# Generated by OpenFakeRAM
VERSION 5.7 ;
BUSBITCHARS "[]" ;
PROPERTYDEFINITIONS
  MACRO width INTEGER ;
  MACRO depth INTEGER ;
  MACRO banks INTEGER ;
END PROPERTYDEFINITIONS
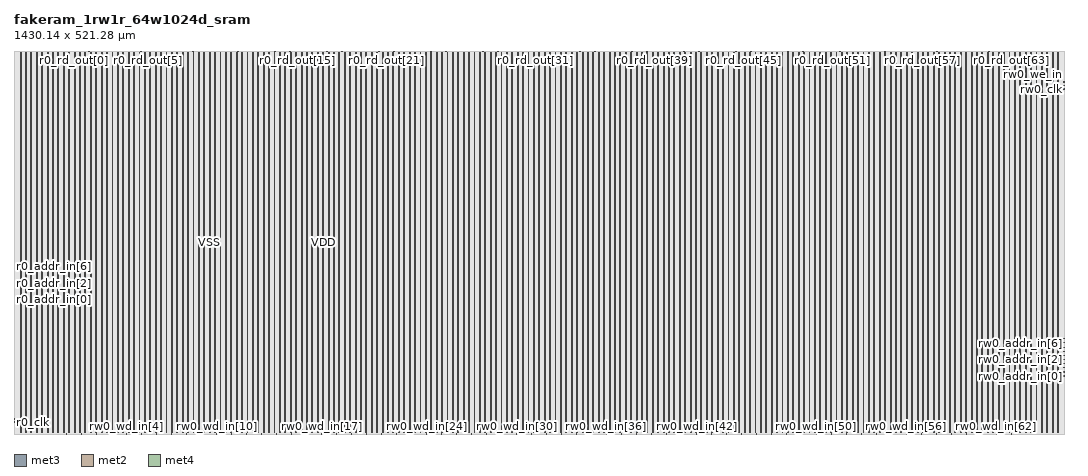
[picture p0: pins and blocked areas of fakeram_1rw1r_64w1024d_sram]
MACRO fakeram_1rw1r_64w1024d_sram
  PROPERTY width 64 ;
  PROPERTY depth 1024 ;
  PROPERTY banks 1 ;
  FOREIGN fakeram_1rw1r_64w1024d_sram 0 0 ;
  SYMMETRY X Y R90 ;
  SIZE 1430.140 BY 521.280 ;
  CLASS BLOCK ;
  PIN r0_clk
    DIRECTION INPUT ;
    USE SIGNAL ;
    SHAPE ABUTMENT ;
    PORT
      LAYER met3 ;
      RECT 0.000 16.170 0.800 16.470 ;
    END
  END r0_clk
  PIN r0_ce_in
    DIRECTION INPUT ;
    USE SIGNAL ;
    SHAPE ABUTMENT ;
    PORT
      LAYER met3 ;
      RECT 0.000 20.250 0.800 20.550 ;
    END
  END r0_ce_in
  PIN r0_addr_in[0]
    DIRECTION INPUT ;
    USE SIGNAL ;
    SHAPE ABUTMENT ;
    PORT
      LAYER met3 ;
      RECT 0.000 182.770 0.800 183.070 ;
    END
  END r0_addr_in[0]
  PIN r0_addr_in[1]
    DIRECTION INPUT ;
    USE SIGNAL ;
    SHAPE ABUTMENT ;
    PORT
      LAYER met3 ;
      RECT 0.000 188.210 0.800 188.510 ;
    END
  END r0_addr_in[1]
  PIN r0_addr_in[2]
    DIRECTION INPUT ;
    USE SIGNAL ;
    SHAPE ABUTMENT ;
    PORT
      LAYER met3 ;
      RECT 0.000 194.330 0.800 194.630 ;
    END
  END r0_addr_in[2]
  PIN r0_addr_in[3]
    DIRECTION INPUT ;
    USE SIGNAL ;
    SHAPE ABUTMENT ;
    PORT
      LAYER met3 ;
      RECT 0.000 199.770 0.800 200.070 ;
    END
  END r0_addr_in[3]
  PIN r0_addr_in[4]
    DIRECTION INPUT ;
    USE SIGNAL ;
    SHAPE ABUTMENT ;
    PORT
      LAYER met3 ;
      RECT 0.000 205.890 0.800 206.190 ;
    END
  END r0_addr_in[4]
  PIN r0_addr_in[5]
    DIRECTION INPUT ;
    USE SIGNAL ;
    SHAPE ABUTMENT ;
    PORT
      LAYER met3 ;
      RECT 0.000 211.330 0.800 211.630 ;
    END
  END r0_addr_in[5]
  PIN r0_addr_in[6]
    DIRECTION INPUT ;
    USE SIGNAL ;
    SHAPE ABUTMENT ;
    PORT
      LAYER met3 ;
      RECT 0.000 217.450 0.800 217.750 ;
    END
  END r0_addr_in[6]
  PIN r0_addr_in[7]
    DIRECTION INPUT ;
    USE SIGNAL ;
    SHAPE ABUTMENT ;
    PORT
      LAYER met3 ;
      RECT 0.000 222.890 0.800 223.190 ;
    END
  END r0_addr_in[7]
  PIN r0_addr_in[8]
    DIRECTION INPUT ;
    USE SIGNAL ;
    SHAPE ABUTMENT ;
    PORT
      LAYER met3 ;
      RECT 0.000 229.010 0.800 229.310 ;
    END
  END r0_addr_in[8]
  PIN r0_addr_in[9]
    DIRECTION INPUT ;
    USE SIGNAL ;
    SHAPE ABUTMENT ;
    PORT
      LAYER met3 ;
      RECT 0.000 234.450 0.800 234.750 ;
    END
  END r0_addr_in[9]
  PIN rw0_rd_out[0]
    DIRECTION OUTPUT ;
    USE SIGNAL ;
    SHAPE ABUTMENT ;
    PORT
      LAYER met2 ;
      RECT 71.610 520.480 71.910 521.280 ;
    END
  END rw0_rd_out[0]
  PIN r0_rd_out[0]
    DIRECTION OUTPUT ;
    USE SIGNAL ;
    SHAPE ABUTMENT ;
    PORT
      LAYER met2 ;
      RECT 81.730 520.480 82.030 521.280 ;
    END
  END r0_rd_out[0]
  PIN rw0_rd_out[1]
    DIRECTION OUTPUT ;
    USE SIGNAL ;
    SHAPE ABUTMENT ;
    PORT
      LAYER met2 ;
      RECT 91.850 520.480 92.150 521.280 ;
    END
  END rw0_rd_out[1]
  PIN r0_rd_out[1]
    DIRECTION OUTPUT ;
    USE SIGNAL ;
    SHAPE ABUTMENT ;
    PORT
      LAYER met2 ;
      RECT 101.970 520.480 102.270 521.280 ;
    END
  END r0_rd_out[1]
  PIN rw0_rd_out[2]
    DIRECTION OUTPUT ;
    USE SIGNAL ;
    SHAPE ABUTMENT ;
    PORT
      LAYER met2 ;
      RECT 112.090 520.480 112.390 521.280 ;
    END
  END rw0_rd_out[2]
  PIN r0_rd_out[2]
    DIRECTION OUTPUT ;
    USE SIGNAL ;
    SHAPE ABUTMENT ;
    PORT
      LAYER met2 ;
      RECT 122.210 520.480 122.510 521.280 ;
    END
  END r0_rd_out[2]
  PIN rw0_rd_out[3]
    DIRECTION OUTPUT ;
    USE SIGNAL ;
    SHAPE ABUTMENT ;
    PORT
      LAYER met2 ;
      RECT 132.330 520.480 132.630 521.280 ;
    END
  END rw0_rd_out[3]
  PIN r0_rd_out[3]
    DIRECTION OUTPUT ;
    USE SIGNAL ;
    SHAPE ABUTMENT ;
    PORT
      LAYER met2 ;
      RECT 142.450 520.480 142.750 521.280 ;
    END
  END r0_rd_out[3]
  PIN rw0_rd_out[4]
    DIRECTION OUTPUT ;
    USE SIGNAL ;
    SHAPE ABUTMENT ;
    PORT
      LAYER met2 ;
      RECT 152.570 520.480 152.870 521.280 ;
    END
  END rw0_rd_out[4]
  PIN r0_rd_out[4]
    DIRECTION OUTPUT ;
    USE SIGNAL ;
    SHAPE ABUTMENT ;
    PORT
      LAYER met2 ;
      RECT 162.690 520.480 162.990 521.280 ;
    END
  END r0_rd_out[4]
  PIN rw0_rd_out[5]
    DIRECTION OUTPUT ;
    USE SIGNAL ;
    SHAPE ABUTMENT ;
    PORT
      LAYER met2 ;
      RECT 172.810 520.480 173.110 521.280 ;
    END
  END rw0_rd_out[5]
  PIN r0_rd_out[5]
    DIRECTION OUTPUT ;
    USE SIGNAL ;
    SHAPE ABUTMENT ;
    PORT
      LAYER met2 ;
      RECT 182.930 520.480 183.230 521.280 ;
    END
  END r0_rd_out[5]
  PIN rw0_rd_out[6]
    DIRECTION OUTPUT ;
    USE SIGNAL ;
    SHAPE ABUTMENT ;
    PORT
      LAYER met2 ;
      RECT 193.050 520.480 193.350 521.280 ;
    END
  END rw0_rd_out[6]
  PIN r0_rd_out[6]
    DIRECTION OUTPUT ;
    USE SIGNAL ;
    SHAPE ABUTMENT ;
    PORT
      LAYER met2 ;
      RECT 203.170 520.480 203.470 521.280 ;
    END
  END r0_rd_out[6]
  PIN rw0_rd_out[7]
    DIRECTION OUTPUT ;
    USE SIGNAL ;
    SHAPE ABUTMENT ;
    PORT
      LAYER met2 ;
      RECT 213.290 520.480 213.590 521.280 ;
    END
  END rw0_rd_out[7]
  PIN r0_rd_out[7]
    DIRECTION OUTPUT ;
    USE SIGNAL ;
    SHAPE ABUTMENT ;
    PORT
      LAYER met2 ;
      RECT 223.410 520.480 223.710 521.280 ;
    END
  END r0_rd_out[7]
  PIN rw0_rd_out[8]
    DIRECTION OUTPUT ;
    USE SIGNAL ;
    SHAPE ABUTMENT ;
    PORT
      LAYER met2 ;
      RECT 233.530 520.480 233.830 521.280 ;
    END
  END rw0_rd_out[8]
  PIN r0_rd_out[8]
    DIRECTION OUTPUT ;
    USE SIGNAL ;
    SHAPE ABUTMENT ;
    PORT
      LAYER met2 ;
      RECT 243.650 520.480 243.950 521.280 ;
    END
  END r0_rd_out[8]
  PIN rw0_rd_out[9]
    DIRECTION OUTPUT ;
    USE SIGNAL ;
    SHAPE ABUTMENT ;
    PORT
      LAYER met2 ;
      RECT 253.770 520.480 254.070 521.280 ;
    END
  END rw0_rd_out[9]
  PIN r0_rd_out[9]
    DIRECTION OUTPUT ;
    USE SIGNAL ;
    SHAPE ABUTMENT ;
    PORT
      LAYER met2 ;
      RECT 263.890 520.480 264.190 521.280 ;
    END
  END r0_rd_out[9]
  PIN rw0_rd_out[10]
    DIRECTION OUTPUT ;
    USE SIGNAL ;
    SHAPE ABUTMENT ;
    PORT
      LAYER met2 ;
      RECT 274.010 520.480 274.310 521.280 ;
    END
  END rw0_rd_out[10]
  PIN r0_rd_out[10]
    DIRECTION OUTPUT ;
    USE SIGNAL ;
    SHAPE ABUTMENT ;
    PORT
      LAYER met2 ;
      RECT 284.130 520.480 284.430 521.280 ;
    END
  END r0_rd_out[10]
  PIN rw0_rd_out[11]
    DIRECTION OUTPUT ;
    USE SIGNAL ;
    SHAPE ABUTMENT ;
    PORT
      LAYER met2 ;
      RECT 294.710 520.480 295.010 521.280 ;
    END
  END rw0_rd_out[11]
  PIN r0_rd_out[11]
    DIRECTION OUTPUT ;
    USE SIGNAL ;
    SHAPE ABUTMENT ;
    PORT
      LAYER met2 ;
      RECT 304.830 520.480 305.130 521.280 ;
    END
  END r0_rd_out[11]
  PIN rw0_rd_out[12]
    DIRECTION OUTPUT ;
    USE SIGNAL ;
    SHAPE ABUTMENT ;
    PORT
      LAYER met2 ;
      RECT 314.950 520.480 315.250 521.280 ;
    END
  END rw0_rd_out[12]
  PIN r0_rd_out[12]
    DIRECTION OUTPUT ;
    USE SIGNAL ;
    SHAPE ABUTMENT ;
    PORT
      LAYER met2 ;
      RECT 325.070 520.480 325.370 521.280 ;
    END
  END r0_rd_out[12]
  PIN rw0_rd_out[13]
    DIRECTION OUTPUT ;
    USE SIGNAL ;
    SHAPE ABUTMENT ;
    PORT
      LAYER met2 ;
      RECT 335.190 520.480 335.490 521.280 ;
    END
  END rw0_rd_out[13]
  PIN r0_rd_out[13]
    DIRECTION OUTPUT ;
    USE SIGNAL ;
    SHAPE ABUTMENT ;
    PORT
      LAYER met2 ;
      RECT 345.310 520.480 345.610 521.280 ;
    END
  END r0_rd_out[13]
  PIN rw0_rd_out[14]
    DIRECTION OUTPUT ;
    USE SIGNAL ;
    SHAPE ABUTMENT ;
    PORT
      LAYER met2 ;
      RECT 355.430 520.480 355.730 521.280 ;
    END
  END rw0_rd_out[14]
  PIN r0_rd_out[14]
    DIRECTION OUTPUT ;
    USE SIGNAL ;
    SHAPE ABUTMENT ;
    PORT
      LAYER met2 ;
      RECT 365.550 520.480 365.850 521.280 ;
    END
  END r0_rd_out[14]
  PIN rw0_rd_out[15]
    DIRECTION OUTPUT ;
    USE SIGNAL ;
    SHAPE ABUTMENT ;
    PORT
      LAYER met2 ;
      RECT 375.670 520.480 375.970 521.280 ;
    END
  END rw0_rd_out[15]
  PIN r0_rd_out[15]
    DIRECTION OUTPUT ;
    USE SIGNAL ;
    SHAPE ABUTMENT ;
    PORT
      LAYER met2 ;
      RECT 385.790 520.480 386.090 521.280 ;
    END
  END r0_rd_out[15]
  PIN rw0_rd_out[16]
    DIRECTION OUTPUT ;
    USE SIGNAL ;
    SHAPE ABUTMENT ;
    PORT
      LAYER met2 ;
      RECT 395.910 520.480 396.210 521.280 ;
    END
  END rw0_rd_out[16]
  PIN r0_rd_out[16]
    DIRECTION OUTPUT ;
    USE SIGNAL ;
    SHAPE ABUTMENT ;
    PORT
      LAYER met2 ;
      RECT 406.030 520.480 406.330 521.280 ;
    END
  END r0_rd_out[16]
  PIN rw0_rd_out[17]
    DIRECTION OUTPUT ;
    USE SIGNAL ;
    SHAPE ABUTMENT ;
    PORT
      LAYER met2 ;
      RECT 416.150 520.480 416.450 521.280 ;
    END
  END rw0_rd_out[17]
  PIN r0_rd_out[17]
    DIRECTION OUTPUT ;
    USE SIGNAL ;
    SHAPE ABUTMENT ;
    PORT
      LAYER met2 ;
      RECT 426.270 520.480 426.570 521.280 ;
    END
  END r0_rd_out[17]
  PIN rw0_rd_out[18]
    DIRECTION OUTPUT ;
    USE SIGNAL ;
    SHAPE ABUTMENT ;
    PORT
      LAYER met2 ;
      RECT 436.390 520.480 436.690 521.280 ;
    END
  END rw0_rd_out[18]
  PIN r0_rd_out[18]
    DIRECTION OUTPUT ;
    USE SIGNAL ;
    SHAPE ABUTMENT ;
    PORT
      LAYER met2 ;
      RECT 446.510 520.480 446.810 521.280 ;
    END
  END r0_rd_out[18]
  PIN rw0_rd_out[19]
    DIRECTION OUTPUT ;
    USE SIGNAL ;
    SHAPE ABUTMENT ;
    PORT
      LAYER met2 ;
      RECT 456.630 520.480 456.930 521.280 ;
    END
  END rw0_rd_out[19]
  PIN r0_rd_out[19]
    DIRECTION OUTPUT ;
    USE SIGNAL ;
    SHAPE ABUTMENT ;
    PORT
      LAYER met2 ;
      RECT 466.750 520.480 467.050 521.280 ;
    END
  END r0_rd_out[19]
  PIN rw0_rd_out[20]
    DIRECTION OUTPUT ;
    USE SIGNAL ;
    SHAPE ABUTMENT ;
    PORT
      LAYER met2 ;
      RECT 476.870 520.480 477.170 521.280 ;
    END
  END rw0_rd_out[20]
  PIN r0_rd_out[20]
    DIRECTION OUTPUT ;
    USE SIGNAL ;
    SHAPE ABUTMENT ;
    PORT
      LAYER met2 ;
      RECT 486.990 520.480 487.290 521.280 ;
    END
  END r0_rd_out[20]
  PIN rw0_rd_out[21]
    DIRECTION OUTPUT ;
    USE SIGNAL ;
    SHAPE ABUTMENT ;
    PORT
      LAYER met2 ;
      RECT 497.110 520.480 497.410 521.280 ;
    END
  END rw0_rd_out[21]
  PIN r0_rd_out[21]
    DIRECTION OUTPUT ;
    USE SIGNAL ;
    SHAPE ABUTMENT ;
    PORT
      LAYER met2 ;
      RECT 507.230 520.480 507.530 521.280 ;
    END
  END r0_rd_out[21]
  PIN rw0_rd_out[22]
    DIRECTION OUTPUT ;
    USE SIGNAL ;
    SHAPE ABUTMENT ;
    PORT
      LAYER met2 ;
      RECT 517.350 520.480 517.650 521.280 ;
    END
  END rw0_rd_out[22]
  PIN r0_rd_out[22]
    DIRECTION OUTPUT ;
    USE SIGNAL ;
    SHAPE ABUTMENT ;
    PORT
      LAYER met2 ;
      RECT 527.470 520.480 527.770 521.280 ;
    END
  END r0_rd_out[22]
  PIN rw0_rd_out[23]
    DIRECTION OUTPUT ;
    USE SIGNAL ;
    SHAPE ABUTMENT ;
    PORT
      LAYER met2 ;
      RECT 537.590 520.480 537.890 521.280 ;
    END
  END rw0_rd_out[23]
  PIN r0_rd_out[23]
    DIRECTION OUTPUT ;
    USE SIGNAL ;
    SHAPE ABUTMENT ;
    PORT
      LAYER met2 ;
      RECT 547.710 520.480 548.010 521.280 ;
    END
  END r0_rd_out[23]
  PIN rw0_rd_out[24]
    DIRECTION OUTPUT ;
    USE SIGNAL ;
    SHAPE ABUTMENT ;
    PORT
      LAYER met2 ;
      RECT 557.830 520.480 558.130 521.280 ;
    END
  END rw0_rd_out[24]
  PIN r0_rd_out[24]
    DIRECTION OUTPUT ;
    USE SIGNAL ;
    SHAPE ABUTMENT ;
    PORT
      LAYER met2 ;
      RECT 567.950 520.480 568.250 521.280 ;
    END
  END r0_rd_out[24]
  PIN rw0_rd_out[25]
    DIRECTION OUTPUT ;
    USE SIGNAL ;
    SHAPE ABUTMENT ;
    PORT
      LAYER met2 ;
      RECT 578.070 520.480 578.370 521.280 ;
    END
  END rw0_rd_out[25]
  PIN r0_rd_out[25]
    DIRECTION OUTPUT ;
    USE SIGNAL ;
    SHAPE ABUTMENT ;
    PORT
      LAYER met2 ;
      RECT 588.190 520.480 588.490 521.280 ;
    END
  END r0_rd_out[25]
  PIN rw0_rd_out[26]
    DIRECTION OUTPUT ;
    USE SIGNAL ;
    SHAPE ABUTMENT ;
    PORT
      LAYER met2 ;
      RECT 598.310 520.480 598.610 521.280 ;
    END
  END rw0_rd_out[26]
  PIN r0_rd_out[26]
    DIRECTION OUTPUT ;
    USE SIGNAL ;
    SHAPE ABUTMENT ;
    PORT
      LAYER met2 ;
      RECT 608.430 520.480 608.730 521.280 ;
    END
  END r0_rd_out[26]
  PIN rw0_rd_out[27]
    DIRECTION OUTPUT ;
    USE SIGNAL ;
    SHAPE ABUTMENT ;
    PORT
      LAYER met2 ;
      RECT 618.550 520.480 618.850 521.280 ;
    END
  END rw0_rd_out[27]
  PIN r0_rd_out[27]
    DIRECTION OUTPUT ;
    USE SIGNAL ;
    SHAPE ABUTMENT ;
    PORT
      LAYER met2 ;
      RECT 628.670 520.480 628.970 521.280 ;
    END
  END r0_rd_out[27]
  PIN rw0_rd_out[28]
    DIRECTION OUTPUT ;
    USE SIGNAL ;
    SHAPE ABUTMENT ;
    PORT
      LAYER met2 ;
      RECT 638.790 520.480 639.090 521.280 ;
    END
  END rw0_rd_out[28]
  PIN r0_rd_out[28]
    DIRECTION OUTPUT ;
    USE SIGNAL ;
    SHAPE ABUTMENT ;
    PORT
      LAYER met2 ;
      RECT 648.910 520.480 649.210 521.280 ;
    END
  END r0_rd_out[28]
  PIN rw0_rd_out[29]
    DIRECTION OUTPUT ;
    USE SIGNAL ;
    SHAPE ABUTMENT ;
    PORT
      LAYER met2 ;
      RECT 659.030 520.480 659.330 521.280 ;
    END
  END rw0_rd_out[29]
  PIN r0_rd_out[29]
    DIRECTION OUTPUT ;
    USE SIGNAL ;
    SHAPE ABUTMENT ;
    PORT
      LAYER met2 ;
      RECT 669.150 520.480 669.450 521.280 ;
    END
  END r0_rd_out[29]
  PIN rw0_rd_out[30]
    DIRECTION OUTPUT ;
    USE SIGNAL ;
    SHAPE ABUTMENT ;
    PORT
      LAYER met2 ;
      RECT 679.270 520.480 679.570 521.280 ;
    END
  END rw0_rd_out[30]
  PIN r0_rd_out[30]
    DIRECTION OUTPUT ;
    USE SIGNAL ;
    SHAPE ABUTMENT ;
    PORT
      LAYER met2 ;
      RECT 689.390 520.480 689.690 521.280 ;
    END
  END r0_rd_out[30]
  PIN rw0_rd_out[31]
    DIRECTION OUTPUT ;
    USE SIGNAL ;
    SHAPE ABUTMENT ;
    PORT
      LAYER met2 ;
      RECT 699.510 520.480 699.810 521.280 ;
    END
  END rw0_rd_out[31]
  PIN r0_rd_out[31]
    DIRECTION OUTPUT ;
    USE SIGNAL ;
    SHAPE ABUTMENT ;
    PORT
      LAYER met2 ;
      RECT 709.630 520.480 709.930 521.280 ;
    END
  END r0_rd_out[31]
  PIN rw0_rd_out[32]
    DIRECTION OUTPUT ;
    USE SIGNAL ;
    SHAPE ABUTMENT ;
    PORT
      LAYER met2 ;
      RECT 720.210 520.480 720.510 521.280 ;
    END
  END rw0_rd_out[32]
  PIN r0_rd_out[32]
    DIRECTION OUTPUT ;
    USE SIGNAL ;
    SHAPE ABUTMENT ;
    PORT
      LAYER met2 ;
      RECT 730.330 520.480 730.630 521.280 ;
    END
  END r0_rd_out[32]
  PIN rw0_rd_out[33]
    DIRECTION OUTPUT ;
    USE SIGNAL ;
    SHAPE ABUTMENT ;
    PORT
      LAYER met2 ;
      RECT 740.450 520.480 740.750 521.280 ;
    END
  END rw0_rd_out[33]
  PIN r0_rd_out[33]
    DIRECTION OUTPUT ;
    USE SIGNAL ;
    SHAPE ABUTMENT ;
    PORT
      LAYER met2 ;
      RECT 750.570 520.480 750.870 521.280 ;
    END
  END r0_rd_out[33]
  PIN rw0_rd_out[34]
    DIRECTION OUTPUT ;
    USE SIGNAL ;
    SHAPE ABUTMENT ;
    PORT
      LAYER met2 ;
      RECT 760.690 520.480 760.990 521.280 ;
    END
  END rw0_rd_out[34]
  PIN r0_rd_out[34]
    DIRECTION OUTPUT ;
    USE SIGNAL ;
    SHAPE ABUTMENT ;
    PORT
      LAYER met2 ;
      RECT 770.810 520.480 771.110 521.280 ;
    END
  END r0_rd_out[34]
  PIN rw0_rd_out[35]
    DIRECTION OUTPUT ;
    USE SIGNAL ;
    SHAPE ABUTMENT ;
    PORT
      LAYER met2 ;
      RECT 780.930 520.480 781.230 521.280 ;
    END
  END rw0_rd_out[35]
  PIN r0_rd_out[35]
    DIRECTION OUTPUT ;
    USE SIGNAL ;
    SHAPE ABUTMENT ;
    PORT
      LAYER met2 ;
      RECT 791.050 520.480 791.350 521.280 ;
    END
  END r0_rd_out[35]
  PIN rw0_rd_out[36]
    DIRECTION OUTPUT ;
    USE SIGNAL ;
    SHAPE ABUTMENT ;
    PORT
      LAYER met2 ;
      RECT 801.170 520.480 801.470 521.280 ;
    END
  END rw0_rd_out[36]
  PIN r0_rd_out[36]
    DIRECTION OUTPUT ;
    USE SIGNAL ;
    SHAPE ABUTMENT ;
    PORT
      LAYER met2 ;
      RECT 811.290 520.480 811.590 521.280 ;
    END
  END r0_rd_out[36]
  PIN rw0_rd_out[37]
    DIRECTION OUTPUT ;
    USE SIGNAL ;
    SHAPE ABUTMENT ;
    PORT
      LAYER met2 ;
      RECT 821.410 520.480 821.710 521.280 ;
    END
  END rw0_rd_out[37]
  PIN r0_rd_out[37]
    DIRECTION OUTPUT ;
    USE SIGNAL ;
    SHAPE ABUTMENT ;
    PORT
      LAYER met2 ;
      RECT 831.530 520.480 831.830 521.280 ;
    END
  END r0_rd_out[37]
  PIN rw0_rd_out[38]
    DIRECTION OUTPUT ;
    USE SIGNAL ;
    SHAPE ABUTMENT ;
    PORT
      LAYER met2 ;
      RECT 841.650 520.480 841.950 521.280 ;
    END
  END rw0_rd_out[38]
  PIN r0_rd_out[38]
    DIRECTION OUTPUT ;
    USE SIGNAL ;
    SHAPE ABUTMENT ;
    PORT
      LAYER met2 ;
      RECT 851.770 520.480 852.070 521.280 ;
    END
  END r0_rd_out[38]
  PIN rw0_rd_out[39]
    DIRECTION OUTPUT ;
    USE SIGNAL ;
    SHAPE ABUTMENT ;
    PORT
      LAYER met2 ;
      RECT 861.890 520.480 862.190 521.280 ;
    END
  END rw0_rd_out[39]
  PIN r0_rd_out[39]
    DIRECTION OUTPUT ;
    USE SIGNAL ;
    SHAPE ABUTMENT ;
    PORT
      LAYER met2 ;
      RECT 872.010 520.480 872.310 521.280 ;
    END
  END r0_rd_out[39]
  PIN rw0_rd_out[40]
    DIRECTION OUTPUT ;
    USE SIGNAL ;
    SHAPE ABUTMENT ;
    PORT
      LAYER met2 ;
      RECT 882.130 520.480 882.430 521.280 ;
    END
  END rw0_rd_out[40]
  PIN r0_rd_out[40]
    DIRECTION OUTPUT ;
    USE SIGNAL ;
    SHAPE ABUTMENT ;
    PORT
      LAYER met2 ;
      RECT 892.250 520.480 892.550 521.280 ;
    END
  END r0_rd_out[40]
  PIN rw0_rd_out[41]
    DIRECTION OUTPUT ;
    USE SIGNAL ;
    SHAPE ABUTMENT ;
    PORT
      LAYER met2 ;
      RECT 902.370 520.480 902.670 521.280 ;
    END
  END rw0_rd_out[41]
  PIN r0_rd_out[41]
    DIRECTION OUTPUT ;
    USE SIGNAL ;
    SHAPE ABUTMENT ;
    PORT
      LAYER met2 ;
      RECT 912.490 520.480 912.790 521.280 ;
    END
  END r0_rd_out[41]
  PIN rw0_rd_out[42]
    DIRECTION OUTPUT ;
    USE SIGNAL ;
    SHAPE ABUTMENT ;
    PORT
      LAYER met2 ;
      RECT 922.610 520.480 922.910 521.280 ;
    END
  END rw0_rd_out[42]
  PIN r0_rd_out[42]
    DIRECTION OUTPUT ;
    USE SIGNAL ;
    SHAPE ABUTMENT ;
    PORT
      LAYER met2 ;
      RECT 932.730 520.480 933.030 521.280 ;
    END
  END r0_rd_out[42]
  PIN rw0_rd_out[43]
    DIRECTION OUTPUT ;
    USE SIGNAL ;
    SHAPE ABUTMENT ;
    PORT
      LAYER met2 ;
      RECT 942.850 520.480 943.150 521.280 ;
    END
  END rw0_rd_out[43]
  PIN r0_rd_out[43]
    DIRECTION OUTPUT ;
    USE SIGNAL ;
    SHAPE ABUTMENT ;
    PORT
      LAYER met2 ;
      RECT 952.970 520.480 953.270 521.280 ;
    END
  END r0_rd_out[43]
  PIN rw0_rd_out[44]
    DIRECTION OUTPUT ;
    USE SIGNAL ;
    SHAPE ABUTMENT ;
    PORT
      LAYER met2 ;
      RECT 963.090 520.480 963.390 521.280 ;
    END
  END rw0_rd_out[44]
  PIN r0_rd_out[44]
    DIRECTION OUTPUT ;
    USE SIGNAL ;
    SHAPE ABUTMENT ;
    PORT
      LAYER met2 ;
      RECT 973.210 520.480 973.510 521.280 ;
    END
  END r0_rd_out[44]
  PIN rw0_rd_out[45]
    DIRECTION OUTPUT ;
    USE SIGNAL ;
    SHAPE ABUTMENT ;
    PORT
      LAYER met2 ;
      RECT 983.330 520.480 983.630 521.280 ;
    END
  END rw0_rd_out[45]
  PIN r0_rd_out[45]
    DIRECTION OUTPUT ;
    USE SIGNAL ;
    SHAPE ABUTMENT ;
    PORT
      LAYER met2 ;
      RECT 993.450 520.480 993.750 521.280 ;
    END
  END r0_rd_out[45]
  PIN rw0_rd_out[46]
    DIRECTION OUTPUT ;
    USE SIGNAL ;
    SHAPE ABUTMENT ;
    PORT
      LAYER met2 ;
      RECT 1003.570 520.480 1003.870 521.280 ;
    END
  END rw0_rd_out[46]
  PIN r0_rd_out[46]
    DIRECTION OUTPUT ;
    USE SIGNAL ;
    SHAPE ABUTMENT ;
    PORT
      LAYER met2 ;
      RECT 1013.690 520.480 1013.990 521.280 ;
    END
  END r0_rd_out[46]
  PIN rw0_rd_out[47]
    DIRECTION OUTPUT ;
    USE SIGNAL ;
    SHAPE ABUTMENT ;
    PORT
      LAYER met2 ;
      RECT 1023.810 520.480 1024.110 521.280 ;
    END
  END rw0_rd_out[47]
  PIN r0_rd_out[47]
    DIRECTION OUTPUT ;
    USE SIGNAL ;
    SHAPE ABUTMENT ;
    PORT
      LAYER met2 ;
      RECT 1033.930 520.480 1034.230 521.280 ;
    END
  END r0_rd_out[47]
  PIN rw0_rd_out[48]
    DIRECTION OUTPUT ;
    USE SIGNAL ;
    SHAPE ABUTMENT ;
    PORT
      LAYER met2 ;
      RECT 1044.050 520.480 1044.350 521.280 ;
    END
  END rw0_rd_out[48]
  PIN r0_rd_out[48]
    DIRECTION OUTPUT ;
    USE SIGNAL ;
    SHAPE ABUTMENT ;
    PORT
      LAYER met2 ;
      RECT 1054.170 520.480 1054.470 521.280 ;
    END
  END r0_rd_out[48]
  PIN rw0_rd_out[49]
    DIRECTION OUTPUT ;
    USE SIGNAL ;
    SHAPE ABUTMENT ;
    PORT
      LAYER met2 ;
      RECT 1064.290 520.480 1064.590 521.280 ;
    END
  END rw0_rd_out[49]
  PIN r0_rd_out[49]
    DIRECTION OUTPUT ;
    USE SIGNAL ;
    SHAPE ABUTMENT ;
    PORT
      LAYER met2 ;
      RECT 1074.410 520.480 1074.710 521.280 ;
    END
  END r0_rd_out[49]
  PIN rw0_rd_out[50]
    DIRECTION OUTPUT ;
    USE SIGNAL ;
    SHAPE ABUTMENT ;
    PORT
      LAYER met2 ;
      RECT 1084.530 520.480 1084.830 521.280 ;
    END
  END rw0_rd_out[50]
  PIN r0_rd_out[50]
    DIRECTION OUTPUT ;
    USE SIGNAL ;
    SHAPE ABUTMENT ;
    PORT
      LAYER met2 ;
      RECT 1094.650 520.480 1094.950 521.280 ;
    END
  END r0_rd_out[50]
  PIN rw0_rd_out[51]
    DIRECTION OUTPUT ;
    USE SIGNAL ;
    SHAPE ABUTMENT ;
    PORT
      LAYER met2 ;
      RECT 1104.770 520.480 1105.070 521.280 ;
    END
  END rw0_rd_out[51]
  PIN r0_rd_out[51]
    DIRECTION OUTPUT ;
    USE SIGNAL ;
    SHAPE ABUTMENT ;
    PORT
      LAYER met2 ;
      RECT 1114.890 520.480 1115.190 521.280 ;
    END
  END r0_rd_out[51]
  PIN rw0_rd_out[52]
    DIRECTION OUTPUT ;
    USE SIGNAL ;
    SHAPE ABUTMENT ;
    PORT
      LAYER met2 ;
      RECT 1125.010 520.480 1125.310 521.280 ;
    END
  END rw0_rd_out[52]
  PIN r0_rd_out[52]
    DIRECTION OUTPUT ;
    USE SIGNAL ;
    SHAPE ABUTMENT ;
    PORT
      LAYER met2 ;
      RECT 1135.130 520.480 1135.430 521.280 ;
    END
  END r0_rd_out[52]
  PIN rw0_rd_out[53]
    DIRECTION OUTPUT ;
    USE SIGNAL ;
    SHAPE ABUTMENT ;
    PORT
      LAYER met2 ;
      RECT 1145.710 520.480 1146.010 521.280 ;
    END
  END rw0_rd_out[53]
  PIN r0_rd_out[53]
    DIRECTION OUTPUT ;
    USE SIGNAL ;
    SHAPE ABUTMENT ;
    PORT
      LAYER met2 ;
      RECT 1155.830 520.480 1156.130 521.280 ;
    END
  END r0_rd_out[53]
  PIN rw0_rd_out[54]
    DIRECTION OUTPUT ;
    USE SIGNAL ;
    SHAPE ABUTMENT ;
    PORT
      LAYER met2 ;
      RECT 1165.950 520.480 1166.250 521.280 ;
    END
  END rw0_rd_out[54]
  PIN r0_rd_out[54]
    DIRECTION OUTPUT ;
    USE SIGNAL ;
    SHAPE ABUTMENT ;
    PORT
      LAYER met2 ;
      RECT 1176.070 520.480 1176.370 521.280 ;
    END
  END r0_rd_out[54]
  PIN rw0_rd_out[55]
    DIRECTION OUTPUT ;
    USE SIGNAL ;
    SHAPE ABUTMENT ;
    PORT
      LAYER met2 ;
      RECT 1186.190 520.480 1186.490 521.280 ;
    END
  END rw0_rd_out[55]
  PIN r0_rd_out[55]
    DIRECTION OUTPUT ;
    USE SIGNAL ;
    SHAPE ABUTMENT ;
    PORT
      LAYER met2 ;
      RECT 1196.310 520.480 1196.610 521.280 ;
    END
  END r0_rd_out[55]
  PIN rw0_rd_out[56]
    DIRECTION OUTPUT ;
    USE SIGNAL ;
    SHAPE ABUTMENT ;
    PORT
      LAYER met2 ;
      RECT 1206.430 520.480 1206.730 521.280 ;
    END
  END rw0_rd_out[56]
  PIN r0_rd_out[56]
    DIRECTION OUTPUT ;
    USE SIGNAL ;
    SHAPE ABUTMENT ;
    PORT
      LAYER met2 ;
      RECT 1216.550 520.480 1216.850 521.280 ;
    END
  END r0_rd_out[56]
  PIN rw0_rd_out[57]
    DIRECTION OUTPUT ;
    USE SIGNAL ;
    SHAPE ABUTMENT ;
    PORT
      LAYER met2 ;
      RECT 1226.670 520.480 1226.970 521.280 ;
    END
  END rw0_rd_out[57]
  PIN r0_rd_out[57]
    DIRECTION OUTPUT ;
    USE SIGNAL ;
    SHAPE ABUTMENT ;
    PORT
      LAYER met2 ;
      RECT 1236.790 520.480 1237.090 521.280 ;
    END
  END r0_rd_out[57]
  PIN rw0_rd_out[58]
    DIRECTION OUTPUT ;
    USE SIGNAL ;
    SHAPE ABUTMENT ;
    PORT
      LAYER met2 ;
      RECT 1246.910 520.480 1247.210 521.280 ;
    END
  END rw0_rd_out[58]
  PIN r0_rd_out[58]
    DIRECTION OUTPUT ;
    USE SIGNAL ;
    SHAPE ABUTMENT ;
    PORT
      LAYER met2 ;
      RECT 1257.030 520.480 1257.330 521.280 ;
    END
  END r0_rd_out[58]
  PIN rw0_rd_out[59]
    DIRECTION OUTPUT ;
    USE SIGNAL ;
    SHAPE ABUTMENT ;
    PORT
      LAYER met2 ;
      RECT 1267.150 520.480 1267.450 521.280 ;
    END
  END rw0_rd_out[59]
  PIN r0_rd_out[59]
    DIRECTION OUTPUT ;
    USE SIGNAL ;
    SHAPE ABUTMENT ;
    PORT
      LAYER met2 ;
      RECT 1277.270 520.480 1277.570 521.280 ;
    END
  END r0_rd_out[59]
  PIN rw0_rd_out[60]
    DIRECTION OUTPUT ;
    USE SIGNAL ;
    SHAPE ABUTMENT ;
    PORT
      LAYER met2 ;
      RECT 1287.390 520.480 1287.690 521.280 ;
    END
  END rw0_rd_out[60]
  PIN r0_rd_out[60]
    DIRECTION OUTPUT ;
    USE SIGNAL ;
    SHAPE ABUTMENT ;
    PORT
      LAYER met2 ;
      RECT 1297.510 520.480 1297.810 521.280 ;
    END
  END r0_rd_out[60]
  PIN rw0_rd_out[61]
    DIRECTION OUTPUT ;
    USE SIGNAL ;
    SHAPE ABUTMENT ;
    PORT
      LAYER met2 ;
      RECT 1307.630 520.480 1307.930 521.280 ;
    END
  END rw0_rd_out[61]
  PIN r0_rd_out[61]
    DIRECTION OUTPUT ;
    USE SIGNAL ;
    SHAPE ABUTMENT ;
    PORT
      LAYER met2 ;
      RECT 1317.750 520.480 1318.050 521.280 ;
    END
  END r0_rd_out[61]
  PIN rw0_rd_out[62]
    DIRECTION OUTPUT ;
    USE SIGNAL ;
    SHAPE ABUTMENT ;
    PORT
      LAYER met2 ;
      RECT 1327.870 520.480 1328.170 521.280 ;
    END
  END rw0_rd_out[62]
  PIN r0_rd_out[62]
    DIRECTION OUTPUT ;
    USE SIGNAL ;
    SHAPE ABUTMENT ;
    PORT
      LAYER met2 ;
      RECT 1337.990 520.480 1338.290 521.280 ;
    END
  END r0_rd_out[62]
  PIN rw0_rd_out[63]
    DIRECTION OUTPUT ;
    USE SIGNAL ;
    SHAPE ABUTMENT ;
    PORT
      LAYER met2 ;
      RECT 1348.110 520.480 1348.410 521.280 ;
    END
  END rw0_rd_out[63]
  PIN r0_rd_out[63]
    DIRECTION OUTPUT ;
    USE SIGNAL ;
    SHAPE ABUTMENT ;
    PORT
      LAYER met2 ;
      RECT 1358.230 520.480 1358.530 521.280 ;
    END
  END r0_rd_out[63]
  PIN rw0_clk
    DIRECTION INPUT ;
    USE SIGNAL ;
    SHAPE ABUTMENT ;
    PORT
      LAYER met3 ;
      RECT 1429.340 469.730 1430.140 470.030 ;
    END
  END rw0_clk
  PIN rw0_ce_in
    DIRECTION INPUT ;
    USE SIGNAL ;
    SHAPE ABUTMENT ;
    PORT
      LAYER met3 ;
      RECT 1429.340 474.490 1430.140 474.790 ;
    END
  END rw0_ce_in
  PIN rw0_we_in
    DIRECTION INPUT ;
    USE SIGNAL ;
    SHAPE ABUTMENT ;
    PORT
      LAYER met3 ;
      RECT 1429.340 479.250 1430.140 479.550 ;
    END
  END rw0_we_in
  PIN rw0_addr_in[0]
    DIRECTION INPUT ;
    USE SIGNAL ;
    SHAPE ABUTMENT ;
    PORT
      LAYER met3 ;
      RECT 1429.340 78.730 1430.140 79.030 ;
    END
  END rw0_addr_in[0]
  PIN rw0_addr_in[1]
    DIRECTION INPUT ;
    USE SIGNAL ;
    SHAPE ABUTMENT ;
    PORT
      LAYER met3 ;
      RECT 1429.340 84.170 1430.140 84.470 ;
    END
  END rw0_addr_in[1]
  PIN rw0_addr_in[2]
    DIRECTION INPUT ;
    USE SIGNAL ;
    SHAPE ABUTMENT ;
    PORT
      LAYER met3 ;
      RECT 1429.340 90.290 1430.140 90.590 ;
    END
  END rw0_addr_in[2]
  PIN rw0_addr_in[3]
    DIRECTION INPUT ;
    USE SIGNAL ;
    SHAPE ABUTMENT ;
    PORT
      LAYER met3 ;
      RECT 1429.340 95.730 1430.140 96.030 ;
    END
  END rw0_addr_in[3]
  PIN rw0_addr_in[4]
    DIRECTION INPUT ;
    USE SIGNAL ;
    SHAPE ABUTMENT ;
    PORT
      LAYER met3 ;
      RECT 1429.340 101.170 1430.140 101.470 ;
    END
  END rw0_addr_in[4]
  PIN rw0_addr_in[5]
    DIRECTION INPUT ;
    USE SIGNAL ;
    SHAPE ABUTMENT ;
    PORT
      LAYER met3 ;
      RECT 1429.340 107.290 1430.140 107.590 ;
    END
  END rw0_addr_in[5]
  PIN rw0_addr_in[6]
    DIRECTION INPUT ;
    USE SIGNAL ;
    SHAPE ABUTMENT ;
    PORT
      LAYER met3 ;
      RECT 1429.340 112.730 1430.140 113.030 ;
    END
  END rw0_addr_in[6]
  PIN rw0_addr_in[7]
    DIRECTION INPUT ;
    USE SIGNAL ;
    SHAPE ABUTMENT ;
    PORT
      LAYER met3 ;
      RECT 1429.340 118.170 1430.140 118.470 ;
    END
  END rw0_addr_in[7]
  PIN rw0_addr_in[8]
    DIRECTION INPUT ;
    USE SIGNAL ;
    SHAPE ABUTMENT ;
    PORT
      LAYER met3 ;
      RECT 1429.340 124.290 1430.140 124.590 ;
    END
  END rw0_addr_in[8]
  PIN rw0_addr_in[9]
    DIRECTION INPUT ;
    USE SIGNAL ;
    SHAPE ABUTMENT ;
    PORT
      LAYER met3 ;
      RECT 1429.340 129.730 1430.140 130.030 ;
    END
  END rw0_addr_in[9]
  PIN rw0_wd_in[0]
    DIRECTION INPUT ;
    USE SIGNAL ;
    SHAPE ABUTMENT ;
    PORT
      LAYER met2 ;
      RECT 71.610 0.000 71.910 0.800 ;
    END
  END rw0_wd_in[0]
  PIN rw0_wd_in[1]
    DIRECTION INPUT ;
    USE SIGNAL ;
    SHAPE ABUTMENT ;
    PORT
      LAYER met2 ;
      RECT 91.850 0.000 92.150 0.800 ;
    END
  END rw0_wd_in[1]
  PIN rw0_wd_in[2]
    DIRECTION INPUT ;
    USE SIGNAL ;
    SHAPE ABUTMENT ;
    PORT
      LAYER met2 ;
      RECT 112.550 0.000 112.850 0.800 ;
    END
  END rw0_wd_in[2]
  PIN rw0_wd_in[3]
    DIRECTION INPUT ;
    USE SIGNAL ;
    SHAPE ABUTMENT ;
    PORT
      LAYER met2 ;
      RECT 132.790 0.000 133.090 0.800 ;
    END
  END rw0_wd_in[3]
  PIN rw0_wd_in[4]
    DIRECTION INPUT ;
    USE SIGNAL ;
    SHAPE ABUTMENT ;
    PORT
      LAYER met2 ;
      RECT 153.490 0.000 153.790 0.800 ;
    END
  END rw0_wd_in[4]
  PIN rw0_wd_in[5]
    DIRECTION INPUT ;
    USE SIGNAL ;
    SHAPE ABUTMENT ;
    PORT
      LAYER met2 ;
      RECT 173.730 0.000 174.030 0.800 ;
    END
  END rw0_wd_in[5]
  PIN rw0_wd_in[6]
    DIRECTION INPUT ;
    USE SIGNAL ;
    SHAPE ABUTMENT ;
    PORT
      LAYER met2 ;
      RECT 193.970 0.000 194.270 0.800 ;
    END
  END rw0_wd_in[6]
  PIN rw0_wd_in[7]
    DIRECTION INPUT ;
    USE SIGNAL ;
    SHAPE ABUTMENT ;
    PORT
      LAYER met2 ;
      RECT 214.670 0.000 214.970 0.800 ;
    END
  END rw0_wd_in[7]
  PIN rw0_wd_in[8]
    DIRECTION INPUT ;
    USE SIGNAL ;
    SHAPE ABUTMENT ;
    PORT
      LAYER met2 ;
      RECT 234.910 0.000 235.210 0.800 ;
    END
  END rw0_wd_in[8]
  PIN rw0_wd_in[9]
    DIRECTION INPUT ;
    USE SIGNAL ;
    SHAPE ABUTMENT ;
    PORT
      LAYER met2 ;
      RECT 255.610 0.000 255.910 0.800 ;
    END
  END rw0_wd_in[9]
  PIN rw0_wd_in[10]
    DIRECTION INPUT ;
    USE SIGNAL ;
    SHAPE ABUTMENT ;
    PORT
      LAYER met2 ;
      RECT 275.850 0.000 276.150 0.800 ;
    END
  END rw0_wd_in[10]
  PIN rw0_wd_in[11]
    DIRECTION INPUT ;
    USE SIGNAL ;
    SHAPE ABUTMENT ;
    PORT
      LAYER met2 ;
      RECT 296.090 0.000 296.390 0.800 ;
    END
  END rw0_wd_in[11]
  PIN rw0_wd_in[12]
    DIRECTION INPUT ;
    USE SIGNAL ;
    SHAPE ABUTMENT ;
    PORT
      LAYER met2 ;
      RECT 316.790 0.000 317.090 0.800 ;
    END
  END rw0_wd_in[12]
  PIN rw0_wd_in[13]
    DIRECTION INPUT ;
    USE SIGNAL ;
    SHAPE ABUTMENT ;
    PORT
      LAYER met2 ;
      RECT 337.030 0.000 337.330 0.800 ;
    END
  END rw0_wd_in[13]
  PIN rw0_wd_in[14]
    DIRECTION INPUT ;
    USE SIGNAL ;
    SHAPE ABUTMENT ;
    PORT
      LAYER met2 ;
      RECT 357.730 0.000 358.030 0.800 ;
    END
  END rw0_wd_in[14]
  PIN rw0_wd_in[15]
    DIRECTION INPUT ;
    USE SIGNAL ;
    SHAPE ABUTMENT ;
    PORT
      LAYER met2 ;
      RECT 377.970 0.000 378.270 0.800 ;
    END
  END rw0_wd_in[15]
  PIN rw0_wd_in[16]
    DIRECTION INPUT ;
    USE SIGNAL ;
    SHAPE ABUTMENT ;
    PORT
      LAYER met2 ;
      RECT 398.210 0.000 398.510 0.800 ;
    END
  END rw0_wd_in[16]
  PIN rw0_wd_in[17]
    DIRECTION INPUT ;
    USE SIGNAL ;
    SHAPE ABUTMENT ;
    PORT
      LAYER met2 ;
      RECT 418.910 0.000 419.210 0.800 ;
    END
  END rw0_wd_in[17]
  PIN rw0_wd_in[18]
    DIRECTION INPUT ;
    USE SIGNAL ;
    SHAPE ABUTMENT ;
    PORT
      LAYER met2 ;
      RECT 439.150 0.000 439.450 0.800 ;
    END
  END rw0_wd_in[18]
  PIN rw0_wd_in[19]
    DIRECTION INPUT ;
    USE SIGNAL ;
    SHAPE ABUTMENT ;
    PORT
      LAYER met2 ;
      RECT 459.850 0.000 460.150 0.800 ;
    END
  END rw0_wd_in[19]
  PIN rw0_wd_in[20]
    DIRECTION INPUT ;
    USE SIGNAL ;
    SHAPE ABUTMENT ;
    PORT
      LAYER met2 ;
      RECT 480.090 0.000 480.390 0.800 ;
    END
  END rw0_wd_in[20]
  PIN rw0_wd_in[21]
    DIRECTION INPUT ;
    USE SIGNAL ;
    SHAPE ABUTMENT ;
    PORT
      LAYER met2 ;
      RECT 500.330 0.000 500.630 0.800 ;
    END
  END rw0_wd_in[21]
  PIN rw0_wd_in[22]
    DIRECTION INPUT ;
    USE SIGNAL ;
    SHAPE ABUTMENT ;
    PORT
      LAYER met2 ;
      RECT 521.030 0.000 521.330 0.800 ;
    END
  END rw0_wd_in[22]
  PIN rw0_wd_in[23]
    DIRECTION INPUT ;
    USE SIGNAL ;
    SHAPE ABUTMENT ;
    PORT
      LAYER met2 ;
      RECT 541.270 0.000 541.570 0.800 ;
    END
  END rw0_wd_in[23]
  PIN rw0_wd_in[24]
    DIRECTION INPUT ;
    USE SIGNAL ;
    SHAPE ABUTMENT ;
    PORT
      LAYER met2 ;
      RECT 561.970 0.000 562.270 0.800 ;
    END
  END rw0_wd_in[24]
  PIN rw0_wd_in[25]
    DIRECTION INPUT ;
    USE SIGNAL ;
    SHAPE ABUTMENT ;
    PORT
      LAYER met2 ;
      RECT 582.210 0.000 582.510 0.800 ;
    END
  END rw0_wd_in[25]
  PIN rw0_wd_in[26]
    DIRECTION INPUT ;
    USE SIGNAL ;
    SHAPE ABUTMENT ;
    PORT
      LAYER met2 ;
      RECT 602.450 0.000 602.750 0.800 ;
    END
  END rw0_wd_in[26]
  PIN rw0_wd_in[27]
    DIRECTION INPUT ;
    USE SIGNAL ;
    SHAPE ABUTMENT ;
    PORT
      LAYER met2 ;
      RECT 623.150 0.000 623.450 0.800 ;
    END
  END rw0_wd_in[27]
  PIN rw0_wd_in[28]
    DIRECTION INPUT ;
    USE SIGNAL ;
    SHAPE ABUTMENT ;
    PORT
      LAYER met2 ;
      RECT 643.390 0.000 643.690 0.800 ;
    END
  END rw0_wd_in[28]
  PIN rw0_wd_in[29]
    DIRECTION INPUT ;
    USE SIGNAL ;
    SHAPE ABUTMENT ;
    PORT
      LAYER met2 ;
      RECT 664.090 0.000 664.390 0.800 ;
    END
  END rw0_wd_in[29]
  PIN rw0_wd_in[30]
    DIRECTION INPUT ;
    USE SIGNAL ;
    SHAPE ABUTMENT ;
    PORT
      LAYER met2 ;
      RECT 684.330 0.000 684.630 0.800 ;
    END
  END rw0_wd_in[30]
  PIN rw0_wd_in[31]
    DIRECTION INPUT ;
    USE SIGNAL ;
    SHAPE ABUTMENT ;
    PORT
      LAYER met2 ;
      RECT 704.570 0.000 704.870 0.800 ;
    END
  END rw0_wd_in[31]
  PIN rw0_wd_in[32]
    DIRECTION INPUT ;
    USE SIGNAL ;
    SHAPE ABUTMENT ;
    PORT
      LAYER met2 ;
      RECT 725.270 0.000 725.570 0.800 ;
    END
  END rw0_wd_in[32]
  PIN rw0_wd_in[33]
    DIRECTION INPUT ;
    USE SIGNAL ;
    SHAPE ABUTMENT ;
    PORT
      LAYER met2 ;
      RECT 745.510 0.000 745.810 0.800 ;
    END
  END rw0_wd_in[33]
  PIN rw0_wd_in[34]
    DIRECTION INPUT ;
    USE SIGNAL ;
    SHAPE ABUTMENT ;
    PORT
      LAYER met2 ;
      RECT 765.750 0.000 766.050 0.800 ;
    END
  END rw0_wd_in[34]
  PIN rw0_wd_in[35]
    DIRECTION INPUT ;
    USE SIGNAL ;
    SHAPE ABUTMENT ;
    PORT
      LAYER met2 ;
      RECT 786.450 0.000 786.750 0.800 ;
    END
  END rw0_wd_in[35]
  PIN rw0_wd_in[36]
    DIRECTION INPUT ;
    USE SIGNAL ;
    SHAPE ABUTMENT ;
    PORT
      LAYER met2 ;
      RECT 806.690 0.000 806.990 0.800 ;
    END
  END rw0_wd_in[36]
  PIN rw0_wd_in[37]
    DIRECTION INPUT ;
    USE SIGNAL ;
    SHAPE ABUTMENT ;
    PORT
      LAYER met2 ;
      RECT 827.390 0.000 827.690 0.800 ;
    END
  END rw0_wd_in[37]
  PIN rw0_wd_in[38]
    DIRECTION INPUT ;
    USE SIGNAL ;
    SHAPE ABUTMENT ;
    PORT
      LAYER met2 ;
      RECT 847.630 0.000 847.930 0.800 ;
    END
  END rw0_wd_in[38]
  PIN rw0_wd_in[39]
    DIRECTION INPUT ;
    USE SIGNAL ;
    SHAPE ABUTMENT ;
    PORT
      LAYER met2 ;
      RECT 867.870 0.000 868.170 0.800 ;
    END
  END rw0_wd_in[39]
  PIN rw0_wd_in[40]
    DIRECTION INPUT ;
    USE SIGNAL ;
    SHAPE ABUTMENT ;
    PORT
      LAYER met2 ;
      RECT 888.570 0.000 888.870 0.800 ;
    END
  END rw0_wd_in[40]
  PIN rw0_wd_in[41]
    DIRECTION INPUT ;
    USE SIGNAL ;
    SHAPE ABUTMENT ;
    PORT
      LAYER met2 ;
      RECT 908.810 0.000 909.110 0.800 ;
    END
  END rw0_wd_in[41]
  PIN rw0_wd_in[42]
    DIRECTION INPUT ;
    USE SIGNAL ;
    SHAPE ABUTMENT ;
    PORT
      LAYER met2 ;
      RECT 929.510 0.000 929.810 0.800 ;
    END
  END rw0_wd_in[42]
  PIN rw0_wd_in[43]
    DIRECTION INPUT ;
    USE SIGNAL ;
    SHAPE ABUTMENT ;
    PORT
      LAYER met2 ;
      RECT 949.750 0.000 950.050 0.800 ;
    END
  END rw0_wd_in[43]
  PIN rw0_wd_in[44]
    DIRECTION INPUT ;
    USE SIGNAL ;
    SHAPE ABUTMENT ;
    PORT
      LAYER met2 ;
      RECT 969.990 0.000 970.290 0.800 ;
    END
  END rw0_wd_in[44]
  PIN rw0_wd_in[45]
    DIRECTION INPUT ;
    USE SIGNAL ;
    SHAPE ABUTMENT ;
    PORT
      LAYER met2 ;
      RECT 990.690 0.000 990.990 0.800 ;
    END
  END rw0_wd_in[45]
  PIN rw0_wd_in[46]
    DIRECTION INPUT ;
    USE SIGNAL ;
    SHAPE ABUTMENT ;
    PORT
      LAYER met2 ;
      RECT 1010.930 0.000 1011.230 0.800 ;
    END
  END rw0_wd_in[46]
  PIN rw0_wd_in[47]
    DIRECTION INPUT ;
    USE SIGNAL ;
    SHAPE ABUTMENT ;
    PORT
      LAYER met2 ;
      RECT 1031.630 0.000 1031.930 0.800 ;
    END
  END rw0_wd_in[47]
  PIN rw0_wd_in[48]
    DIRECTION INPUT ;
    USE SIGNAL ;
    SHAPE ABUTMENT ;
    PORT
      LAYER met2 ;
      RECT 1051.870 0.000 1052.170 0.800 ;
    END
  END rw0_wd_in[48]
  PIN rw0_wd_in[49]
    DIRECTION INPUT ;
    USE SIGNAL ;
    SHAPE ABUTMENT ;
    PORT
      LAYER met2 ;
      RECT 1072.110 0.000 1072.410 0.800 ;
    END
  END rw0_wd_in[49]
  PIN rw0_wd_in[50]
    DIRECTION INPUT ;
    USE SIGNAL ;
    SHAPE ABUTMENT ;
    PORT
      LAYER met2 ;
      RECT 1092.810 0.000 1093.110 0.800 ;
    END
  END rw0_wd_in[50]
  PIN rw0_wd_in[51]
    DIRECTION INPUT ;
    USE SIGNAL ;
    SHAPE ABUTMENT ;
    PORT
      LAYER met2 ;
      RECT 1113.050 0.000 1113.350 0.800 ;
    END
  END rw0_wd_in[51]
  PIN rw0_wd_in[52]
    DIRECTION INPUT ;
    USE SIGNAL ;
    SHAPE ABUTMENT ;
    PORT
      LAYER met2 ;
      RECT 1133.750 0.000 1134.050 0.800 ;
    END
  END rw0_wd_in[52]
  PIN rw0_wd_in[53]
    DIRECTION INPUT ;
    USE SIGNAL ;
    SHAPE ABUTMENT ;
    PORT
      LAYER met2 ;
      RECT 1153.990 0.000 1154.290 0.800 ;
    END
  END rw0_wd_in[53]
  PIN rw0_wd_in[54]
    DIRECTION INPUT ;
    USE SIGNAL ;
    SHAPE ABUTMENT ;
    PORT
      LAYER met2 ;
      RECT 1174.230 0.000 1174.530 0.800 ;
    END
  END rw0_wd_in[54]
  PIN rw0_wd_in[55]
    DIRECTION INPUT ;
    USE SIGNAL ;
    SHAPE ABUTMENT ;
    PORT
      LAYER met2 ;
      RECT 1194.930 0.000 1195.230 0.800 ;
    END
  END rw0_wd_in[55]
  PIN rw0_wd_in[56]
    DIRECTION INPUT ;
    USE SIGNAL ;
    SHAPE ABUTMENT ;
    PORT
      LAYER met2 ;
      RECT 1215.170 0.000 1215.470 0.800 ;
    END
  END rw0_wd_in[56]
  PIN rw0_wd_in[57]
    DIRECTION INPUT ;
    USE SIGNAL ;
    SHAPE ABUTMENT ;
    PORT
      LAYER met2 ;
      RECT 1235.870 0.000 1236.170 0.800 ;
    END
  END rw0_wd_in[57]
  PIN rw0_wd_in[58]
    DIRECTION INPUT ;
    USE SIGNAL ;
    SHAPE ABUTMENT ;
    PORT
      LAYER met2 ;
      RECT 1256.110 0.000 1256.410 0.800 ;
    END
  END rw0_wd_in[58]
  PIN rw0_wd_in[59]
    DIRECTION INPUT ;
    USE SIGNAL ;
    SHAPE ABUTMENT ;
    PORT
      LAYER met2 ;
      RECT 1276.350 0.000 1276.650 0.800 ;
    END
  END rw0_wd_in[59]
  PIN rw0_wd_in[60]
    DIRECTION INPUT ;
    USE SIGNAL ;
    SHAPE ABUTMENT ;
    PORT
      LAYER met2 ;
      RECT 1297.050 0.000 1297.350 0.800 ;
    END
  END rw0_wd_in[60]
  PIN rw0_wd_in[61]
    DIRECTION INPUT ;
    USE SIGNAL ;
    SHAPE ABUTMENT ;
    PORT
      LAYER met2 ;
      RECT 1317.290 0.000 1317.590 0.800 ;
    END
  END rw0_wd_in[61]
  PIN rw0_wd_in[62]
    DIRECTION INPUT ;
    USE SIGNAL ;
    SHAPE ABUTMENT ;
    PORT
      LAYER met2 ;
      RECT 1337.990 0.000 1338.290 0.800 ;
    END
  END rw0_wd_in[62]
  PIN rw0_wd_in[63]
    DIRECTION INPUT ;
    USE SIGNAL ;
    SHAPE ABUTMENT ;
    PORT
      LAYER met2 ;
      RECT 1358.230 0.000 1358.530 0.800 ;
    END
  END rw0_wd_in[63]
  PIN VSS
    DIRECTION INOUT ;
    USE GROUND ;
    PORT
      LAYER met4 ;
      RECT 15.720 1.600 16.920 519.680 ;
      RECT 30.440 1.600 31.640 519.680 ;
      RECT 45.160 1.600 46.360 519.680 ;
      RECT 59.880 1.600 61.080 519.680 ;
      RECT 74.600 1.600 75.800 519.680 ;
      RECT 89.320 1.600 90.520 519.680 ;
      RECT 104.040 1.600 105.240 519.680 ;
      RECT 118.760 1.600 119.960 519.680 ;
      RECT 133.480 1.600 134.680 519.680 ;
      RECT 148.200 1.600 149.400 519.680 ;
      RECT 162.920 1.600 164.120 519.680 ;
      RECT 177.640 1.600 178.840 519.680 ;
      RECT 192.360 1.600 193.560 519.680 ;
      RECT 207.080 1.600 208.280 519.680 ;
      RECT 221.800 1.600 223.000 519.680 ;
      RECT 236.520 1.600 237.720 519.680 ;
      RECT 251.240 1.600 252.440 519.680 ;
      RECT 265.960 1.600 267.160 519.680 ;
      RECT 280.680 1.600 281.880 519.680 ;
      RECT 295.400 1.600 296.600 519.680 ;
      RECT 310.120 1.600 311.320 519.680 ;
      RECT 324.840 1.600 326.040 519.680 ;
      RECT 339.560 1.600 340.760 519.680 ;
      RECT 354.280 1.600 355.480 519.680 ;
      RECT 369.000 1.600 370.200 519.680 ;
      RECT 383.720 1.600 384.920 519.680 ;
      RECT 398.440 1.600 399.640 519.680 ;
      RECT 413.160 1.600 414.360 519.680 ;
      RECT 427.880 1.600 429.080 519.680 ;
      RECT 442.600 1.600 443.800 519.680 ;
      RECT 457.320 1.600 458.520 519.680 ;
      RECT 472.040 1.600 473.240 519.680 ;
      RECT 486.760 1.600 487.960 519.680 ;
      RECT 501.480 1.600 502.680 519.680 ;
      RECT 516.200 1.600 517.400 519.680 ;
      RECT 530.920 1.600 532.120 519.680 ;
      RECT 545.640 1.600 546.840 519.680 ;
      RECT 560.360 1.600 561.560 519.680 ;
      RECT 575.080 1.600 576.280 519.680 ;
      RECT 589.800 1.600 591.000 519.680 ;
      RECT 604.520 1.600 605.720 519.680 ;
      RECT 619.240 1.600 620.440 519.680 ;
      RECT 633.960 1.600 635.160 519.680 ;
      RECT 648.680 1.600 649.880 519.680 ;
      RECT 663.400 1.600 664.600 519.680 ;
      RECT 678.120 1.600 679.320 519.680 ;
      RECT 692.840 1.600 694.040 519.680 ;
      RECT 707.560 1.600 708.760 519.680 ;
      RECT 722.280 1.600 723.480 519.680 ;
      RECT 737.000 1.600 738.200 519.680 ;
      RECT 751.720 1.600 752.920 519.680 ;
      RECT 766.440 1.600 767.640 519.680 ;
      RECT 781.160 1.600 782.360 519.680 ;
      RECT 795.880 1.600 797.080 519.680 ;
      RECT 810.600 1.600 811.800 519.680 ;
      RECT 825.320 1.600 826.520 519.680 ;
      RECT 840.040 1.600 841.240 519.680 ;
      RECT 854.760 1.600 855.960 519.680 ;
      RECT 869.480 1.600 870.680 519.680 ;
      RECT 884.200 1.600 885.400 519.680 ;
      RECT 898.920 1.600 900.120 519.680 ;
      RECT 913.640 1.600 914.840 519.680 ;
      RECT 928.360 1.600 929.560 519.680 ;
      RECT 943.080 1.600 944.280 519.680 ;
      RECT 957.800 1.600 959.000 519.680 ;
      RECT 972.520 1.600 973.720 519.680 ;
      RECT 987.240 1.600 988.440 519.680 ;
      RECT 1001.960 1.600 1003.160 519.680 ;
      RECT 1016.680 1.600 1017.880 519.680 ;
      RECT 1031.400 1.600 1032.600 519.680 ;
      RECT 1046.120 1.600 1047.320 519.680 ;
      RECT 1060.840 1.600 1062.040 519.680 ;
      RECT 1075.560 1.600 1076.760 519.680 ;
      RECT 1090.280 1.600 1091.480 519.680 ;
      RECT 1105.000 1.600 1106.200 519.680 ;
      RECT 1119.720 1.600 1120.920 519.680 ;
      RECT 1134.440 1.600 1135.640 519.680 ;
      RECT 1149.160 1.600 1150.360 519.680 ;
      RECT 1163.880 1.600 1165.080 519.680 ;
      RECT 1178.600 1.600 1179.800 519.680 ;
      RECT 1193.320 1.600 1194.520 519.680 ;
      RECT 1208.040 1.600 1209.240 519.680 ;
      RECT 1222.760 1.600 1223.960 519.680 ;
      RECT 1237.480 1.600 1238.680 519.680 ;
      RECT 1252.200 1.600 1253.400 519.680 ;
      RECT 1266.920 1.600 1268.120 519.680 ;
      RECT 1281.640 1.600 1282.840 519.680 ;
      RECT 1296.360 1.600 1297.560 519.680 ;
      RECT 1311.080 1.600 1312.280 519.680 ;
      RECT 1325.800 1.600 1327.000 519.680 ;
      RECT 1340.520 1.600 1341.720 519.680 ;
      RECT 1355.240 1.600 1356.440 519.680 ;
      RECT 1369.960 1.600 1371.160 519.680 ;
      RECT 1384.680 1.600 1385.880 519.680 ;
      RECT 1399.400 1.600 1400.600 519.680 ;
      RECT 1414.120 1.600 1415.320 519.680 ;
    END
  END VSS
  PIN VDD
    DIRECTION INOUT ;
    USE POWER ;
    PORT
      LAYER met4 ;
      RECT 8.360 1.600 9.560 519.680 ;
      RECT 23.080 1.600 24.280 519.680 ;
      RECT 37.800 1.600 39.000 519.680 ;
      RECT 52.520 1.600 53.720 519.680 ;
      RECT 67.240 1.600 68.440 519.680 ;
      RECT 81.960 1.600 83.160 519.680 ;
      RECT 96.680 1.600 97.880 519.680 ;
      RECT 111.400 1.600 112.600 519.680 ;
      RECT 126.120 1.600 127.320 519.680 ;
      RECT 140.840 1.600 142.040 519.680 ;
      RECT 155.560 1.600 156.760 519.680 ;
      RECT 170.280 1.600 171.480 519.680 ;
      RECT 185.000 1.600 186.200 519.680 ;
      RECT 199.720 1.600 200.920 519.680 ;
      RECT 214.440 1.600 215.640 519.680 ;
      RECT 229.160 1.600 230.360 519.680 ;
      RECT 243.880 1.600 245.080 519.680 ;
      RECT 258.600 1.600 259.800 519.680 ;
      RECT 273.320 1.600 274.520 519.680 ;
      RECT 288.040 1.600 289.240 519.680 ;
      RECT 302.760 1.600 303.960 519.680 ;
      RECT 317.480 1.600 318.680 519.680 ;
      RECT 332.200 1.600 333.400 519.680 ;
      RECT 346.920 1.600 348.120 519.680 ;
      RECT 361.640 1.600 362.840 519.680 ;
      RECT 376.360 1.600 377.560 519.680 ;
      RECT 391.080 1.600 392.280 519.680 ;
      RECT 405.800 1.600 407.000 519.680 ;
      RECT 420.520 1.600 421.720 519.680 ;
      RECT 435.240 1.600 436.440 519.680 ;
      RECT 449.960 1.600 451.160 519.680 ;
      RECT 464.680 1.600 465.880 519.680 ;
      RECT 479.400 1.600 480.600 519.680 ;
      RECT 494.120 1.600 495.320 519.680 ;
      RECT 508.840 1.600 510.040 519.680 ;
      RECT 523.560 1.600 524.760 519.680 ;
      RECT 538.280 1.600 539.480 519.680 ;
      RECT 553.000 1.600 554.200 519.680 ;
      RECT 567.720 1.600 568.920 519.680 ;
      RECT 582.440 1.600 583.640 519.680 ;
      RECT 597.160 1.600 598.360 519.680 ;
      RECT 611.880 1.600 613.080 519.680 ;
      RECT 626.600 1.600 627.800 519.680 ;
      RECT 641.320 1.600 642.520 519.680 ;
      RECT 656.040 1.600 657.240 519.680 ;
      RECT 670.760 1.600 671.960 519.680 ;
      RECT 685.480 1.600 686.680 519.680 ;
      RECT 700.200 1.600 701.400 519.680 ;
      RECT 714.920 1.600 716.120 519.680 ;
      RECT 729.640 1.600 730.840 519.680 ;
      RECT 744.360 1.600 745.560 519.680 ;
      RECT 759.080 1.600 760.280 519.680 ;
      RECT 773.800 1.600 775.000 519.680 ;
      RECT 788.520 1.600 789.720 519.680 ;
      RECT 803.240 1.600 804.440 519.680 ;
      RECT 817.960 1.600 819.160 519.680 ;
      RECT 832.680 1.600 833.880 519.680 ;
      RECT 847.400 1.600 848.600 519.680 ;
      RECT 862.120 1.600 863.320 519.680 ;
      RECT 876.840 1.600 878.040 519.680 ;
      RECT 891.560 1.600 892.760 519.680 ;
      RECT 906.280 1.600 907.480 519.680 ;
      RECT 921.000 1.600 922.200 519.680 ;
      RECT 935.720 1.600 936.920 519.680 ;
      RECT 950.440 1.600 951.640 519.680 ;
      RECT 965.160 1.600 966.360 519.680 ;
      RECT 979.880 1.600 981.080 519.680 ;
      RECT 994.600 1.600 995.800 519.680 ;
      RECT 1009.320 1.600 1010.520 519.680 ;
      RECT 1024.040 1.600 1025.240 519.680 ;
      RECT 1038.760 1.600 1039.960 519.680 ;
      RECT 1053.480 1.600 1054.680 519.680 ;
      RECT 1068.200 1.600 1069.400 519.680 ;
      RECT 1082.920 1.600 1084.120 519.680 ;
      RECT 1097.640 1.600 1098.840 519.680 ;
      RECT 1112.360 1.600 1113.560 519.680 ;
      RECT 1127.080 1.600 1128.280 519.680 ;
      RECT 1141.800 1.600 1143.000 519.680 ;
      RECT 1156.520 1.600 1157.720 519.680 ;
      RECT 1171.240 1.600 1172.440 519.680 ;
      RECT 1185.960 1.600 1187.160 519.680 ;
      RECT 1200.680 1.600 1201.880 519.680 ;
      RECT 1215.400 1.600 1216.600 519.680 ;
      RECT 1230.120 1.600 1231.320 519.680 ;
      RECT 1244.840 1.600 1246.040 519.680 ;
      RECT 1259.560 1.600 1260.760 519.680 ;
      RECT 1274.280 1.600 1275.480 519.680 ;
      RECT 1289.000 1.600 1290.200 519.680 ;
      RECT 1303.720 1.600 1304.920 519.680 ;
      RECT 1318.440 1.600 1319.640 519.680 ;
      RECT 1333.160 1.600 1334.360 519.680 ;
      RECT 1347.880 1.600 1349.080 519.680 ;
      RECT 1362.600 1.600 1363.800 519.680 ;
      RECT 1377.320 1.600 1378.520 519.680 ;
      RECT 1392.040 1.600 1393.240 519.680 ;
      RECT 1406.760 1.600 1407.960 519.680 ;
      RECT 1421.480 1.600 1422.680 519.680 ;
    END
  END VDD
  OBS
    LAYER met1 ;
    RECT 0 0 1430.140 521.280 ;
    LAYER met2 ;
    RECT 0 0 1430.140 521.280 ;
    LAYER met3 ;
    RECT 0 0 1430.140 521.280 ;
    LAYER met4 ;
    RECT 0 0 1430.140 521.280 ;
    LAYER OVERLAP ;
    RECT 0 0 1430.140 521.280 ;
  END
END fakeram_1rw1r_64w1024d_sram

END LIBRARY
